VERSION 5.8 ;
BUSBITCHARS "[]" ;
DIVIDERCHAR "/" ;
UNITS
  DATABASE MICRONS 1000 ;
END UNITS
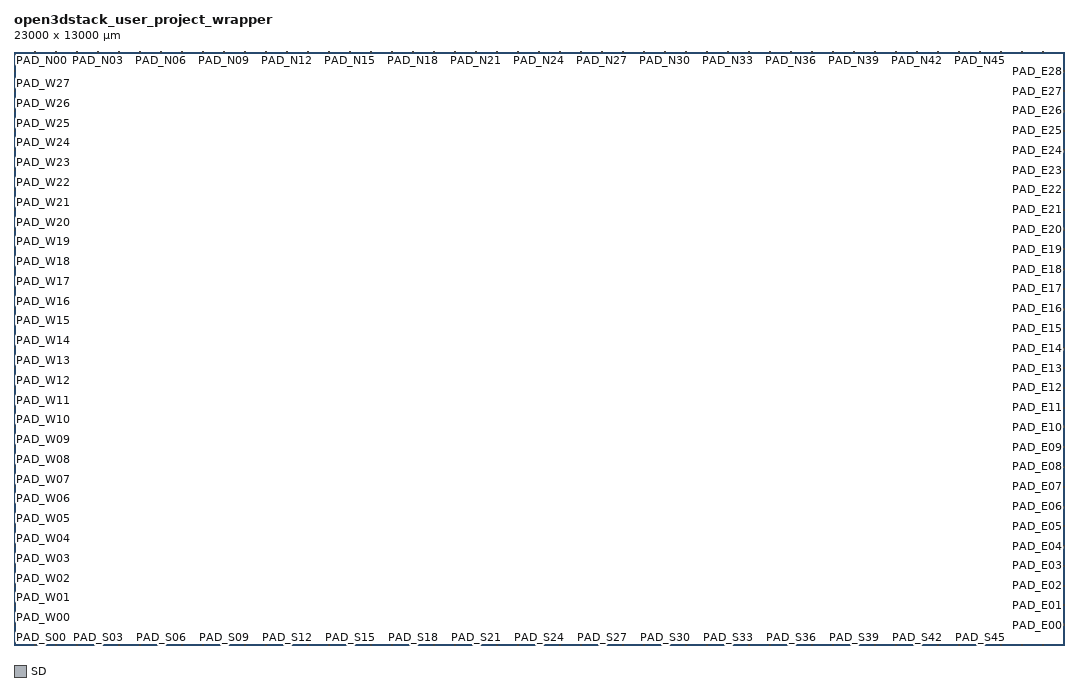
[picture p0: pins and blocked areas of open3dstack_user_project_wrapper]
MACRO open3dstack_user_project_wrapper
  CLASS BLOCK ;
  ORIGIN 0 0 ;
  FOREIGN open3dstack_user_project_wrapper 0 0 ;
  SIZE 23000 BY 13000 ;
  SYMMETRY X Y ;
  PIN PAD_S00
    DIRECTION INOUT ;
    USE SIGNAL ;
    PORT
      LAYER SD ;
        RECT 450 0 470 20 ;
    END
  END PAD_S00
  PIN PAD_S01
    DIRECTION INOUT ;
    USE SIGNAL ;
    PORT
      LAYER SD ;
        RECT 910 0 930 20 ;
    END
  END PAD_S01
  PIN PAD_S02
    DIRECTION INOUT ;
    USE SIGNAL ;
    PORT
      LAYER SD ;
        RECT 1370 0 1390 20 ;
    END
  END PAD_S02
  PIN PAD_S03
    DIRECTION INOUT ;
    USE SIGNAL ;
    PORT
      LAYER SD ;
        RECT 1830 0 1850 20 ;
    END
  END PAD_S03
  PIN PAD_S04
    DIRECTION INOUT ;
    USE SIGNAL ;
    PORT
      LAYER SD ;
        RECT 2290 0 2310 20 ;
    END
  END PAD_S04
  PIN PAD_S05
    DIRECTION INOUT ;
    USE SIGNAL ;
    PORT
      LAYER SD ;
        RECT 2750 0 2770 20 ;
    END
  END PAD_S05
  PIN PAD_S06
    DIRECTION INOUT ;
    USE SIGNAL ;
    PORT
      LAYER SD ;
        RECT 3210 0 3230 20 ;
    END
  END PAD_S06
  PIN PAD_S07
    DIRECTION INOUT ;
    USE SIGNAL ;
    PORT
      LAYER SD ;
        RECT 3670 0 3690 20 ;
    END
  END PAD_S07
  PIN PAD_S08
    DIRECTION INOUT ;
    USE SIGNAL ;
    PORT
      LAYER SD ;
        RECT 4130 0 4150 20 ;
    END
  END PAD_S08
  PIN PAD_S09
    DIRECTION INOUT ;
    USE SIGNAL ;
    PORT
      LAYER SD ;
        RECT 4590 0 4610 20 ;
    END
  END PAD_S09
  PIN PAD_S10
    DIRECTION INOUT ;
    USE SIGNAL ;
    PORT
      LAYER SD ;
        RECT 5050 0 5070 20 ;
    END
  END PAD_S10
  PIN PAD_S11
    DIRECTION INOUT ;
    USE SIGNAL ;
    PORT
      LAYER SD ;
        RECT 5510 0 5530 20 ;
    END
  END PAD_S11
  PIN PAD_S12
    DIRECTION INOUT ;
    USE SIGNAL ;
    PORT
      LAYER SD ;
        RECT 5970 0 5990 20 ;
    END
  END PAD_S12
  PIN PAD_S13
    DIRECTION INOUT ;
    USE SIGNAL ;
    PORT
      LAYER SD ;
        RECT 6430 0 6450 20 ;
    END
  END PAD_S13
  PIN PAD_S14
    DIRECTION INOUT ;
    USE SIGNAL ;
    PORT
      LAYER SD ;
        RECT 6890 0 6910 20 ;
    END
  END PAD_S14
  PIN PAD_S15
    DIRECTION INOUT ;
    USE SIGNAL ;
    PORT
      LAYER SD ;
        RECT 7350 0 7370 20 ;
    END
  END PAD_S15
  PIN PAD_S16
    DIRECTION INOUT ;
    USE SIGNAL ;
    PORT
      LAYER SD ;
        RECT 7810 0 7830 20 ;
    END
  END PAD_S16
  PIN PAD_S17
    DIRECTION INOUT ;
    USE SIGNAL ;
    PORT
      LAYER SD ;
        RECT 8270 0 8290 20 ;
    END
  END PAD_S17
  PIN PAD_S18
    DIRECTION INOUT ;
    USE SIGNAL ;
    PORT
      LAYER SD ;
        RECT 8730 0 8750 20 ;
    END
  END PAD_S18
  PIN PAD_S19
    DIRECTION INOUT ;
    USE SIGNAL ;
    PORT
      LAYER SD ;
        RECT 9190 0 9210 20 ;
    END
  END PAD_S19
  PIN PAD_S20
    DIRECTION INOUT ;
    USE SIGNAL ;
    PORT
      LAYER SD ;
        RECT 9650 0 9670 20 ;
    END
  END PAD_S20
  PIN PAD_S21
    DIRECTION INOUT ;
    USE SIGNAL ;
    PORT
      LAYER SD ;
        RECT 10110 0 10130 20 ;
    END
  END PAD_S21
  PIN PAD_S22
    DIRECTION INOUT ;
    USE SIGNAL ;
    PORT
      LAYER SD ;
        RECT 10570 0 10590 20 ;
    END
  END PAD_S22
  PIN PAD_S23
    DIRECTION INOUT ;
    USE SIGNAL ;
    PORT
      LAYER SD ;
        RECT 11030 0 11050 20 ;
    END
  END PAD_S23
  PIN PAD_S24
    DIRECTION INOUT ;
    USE SIGNAL ;
    PORT
      LAYER SD ;
        RECT 11490 0 11510 20 ;
    END
  END PAD_S24
  PIN PAD_S25
    DIRECTION INOUT ;
    USE SIGNAL ;
    PORT
      LAYER SD ;
        RECT 11950 0 11970 20 ;
    END
  END PAD_S25
  PIN PAD_S26
    DIRECTION INOUT ;
    USE SIGNAL ;
    PORT
      LAYER SD ;
        RECT 12410 0 12430 20 ;
    END
  END PAD_S26
  PIN PAD_S27
    DIRECTION INOUT ;
    USE SIGNAL ;
    PORT
      LAYER SD ;
        RECT 12870 0 12890 20 ;
    END
  END PAD_S27
  PIN PAD_S28
    DIRECTION INOUT ;
    USE SIGNAL ;
    PORT
      LAYER SD ;
        RECT 13330 0 13350 20 ;
    END
  END PAD_S28
  PIN PAD_S29
    DIRECTION INOUT ;
    USE SIGNAL ;
    PORT
      LAYER SD ;
        RECT 13790 0 13810 20 ;
    END
  END PAD_S29
  PIN PAD_S30
    DIRECTION INOUT ;
    USE SIGNAL ;
    PORT
      LAYER SD ;
        RECT 14250 0 14270 20 ;
    END
  END PAD_S30
  PIN PAD_S31
    DIRECTION INOUT ;
    USE SIGNAL ;
    PORT
      LAYER SD ;
        RECT 14710 0 14730 20 ;
    END
  END PAD_S31
  PIN PAD_S32
    DIRECTION INOUT ;
    USE SIGNAL ;
    PORT
      LAYER SD ;
        RECT 15170 0 15190 20 ;
    END
  END PAD_S32
  PIN PAD_S33
    DIRECTION INOUT ;
    USE SIGNAL ;
    PORT
      LAYER SD ;
        RECT 15630 0 15650 20 ;
    END
  END PAD_S33
  PIN PAD_S34
    DIRECTION INOUT ;
    USE SIGNAL ;
    PORT
      LAYER SD ;
        RECT 16090 0 16110 20 ;
    END
  END PAD_S34
  PIN PAD_S35
    DIRECTION INOUT ;
    USE SIGNAL ;
    PORT
      LAYER SD ;
        RECT 16550 0 16570 20 ;
    END
  END PAD_S35
  PIN PAD_S36
    DIRECTION INOUT ;
    USE SIGNAL ;
    PORT
      LAYER SD ;
        RECT 17010 0 17030 20 ;
    END
  END PAD_S36
  PIN PAD_S37
    DIRECTION INOUT ;
    USE SIGNAL ;
    PORT
      LAYER SD ;
        RECT 17470 0 17490 20 ;
    END
  END PAD_S37
  PIN PAD_S38
    DIRECTION INOUT ;
    USE SIGNAL ;
    PORT
      LAYER SD ;
        RECT 17930 0 17950 20 ;
    END
  END PAD_S38
  PIN PAD_S39
    DIRECTION INOUT ;
    USE SIGNAL ;
    PORT
      LAYER SD ;
        RECT 18390 0 18410 20 ;
    END
  END PAD_S39
  PIN PAD_S40
    DIRECTION INOUT ;
    USE SIGNAL ;
    PORT
      LAYER SD ;
        RECT 18850 0 18870 20 ;
    END
  END PAD_S40
  PIN PAD_S41
    DIRECTION INOUT ;
    USE SIGNAL ;
    PORT
      LAYER SD ;
        RECT 19310 0 19330 20 ;
    END
  END PAD_S41
  PIN PAD_S42
    DIRECTION INOUT ;
    USE SIGNAL ;
    PORT
      LAYER SD ;
        RECT 19770 0 19790 20 ;
    END
  END PAD_S42
  PIN PAD_S43
    DIRECTION INOUT ;
    USE SIGNAL ;
    PORT
      LAYER SD ;
        RECT 20230 0 20250 20 ;
    END
  END PAD_S43
  PIN PAD_S44
    DIRECTION INOUT ;
    USE SIGNAL ;
    PORT
      LAYER SD ;
        RECT 20690 0 20710 20 ;
    END
  END PAD_S44
  PIN PAD_S45
    DIRECTION INOUT ;
    USE SIGNAL ;
    PORT
      LAYER SD ;
        RECT 21150 0 21170 20 ;
    END
  END PAD_S45
  PIN PAD_S46
    DIRECTION INOUT ;
    USE SIGNAL ;
    PORT
      LAYER SD ;
        RECT 21610 0 21630 20 ;
    END
  END PAD_S46
  PIN PAD_S47
    DIRECTION INOUT ;
    USE SIGNAL ;
    PORT
      LAYER SD ;
        RECT 22070 0 22090 20 ;
    END
  END PAD_S47
  PIN PAD_S48
    DIRECTION INOUT ;
    USE SIGNAL ;
    PORT
      LAYER SD ;
        RECT 22530 0 22550 20 ;
    END
  END PAD_S48
  PIN PAD_E00
    DIRECTION INOUT ;
    USE SIGNAL ;
    PORT
      LAYER SD ;
        RECT 22980 423.333 23000 443.333 ;
    END
  END PAD_E00
  PIN PAD_E01
    DIRECTION INOUT ;
    USE SIGNAL ;
    PORT
      LAYER SD ;
        RECT 22980 856.667 23000 876.667 ;
    END
  END PAD_E01
  PIN PAD_E02
    DIRECTION INOUT ;
    USE SIGNAL ;
    PORT
      LAYER SD ;
        RECT 22980 1290 23000 1310 ;
    END
  END PAD_E02
  PIN PAD_E03
    DIRECTION INOUT ;
    USE SIGNAL ;
    PORT
      LAYER SD ;
        RECT 22980 1723.333 23000 1743.333 ;
    END
  END PAD_E03
  PIN PAD_E04
    DIRECTION INOUT ;
    USE SIGNAL ;
    PORT
      LAYER SD ;
        RECT 22980 2156.667 23000 2176.667 ;
    END
  END PAD_E04
  PIN PAD_E05
    DIRECTION INOUT ;
    USE SIGNAL ;
    PORT
      LAYER SD ;
        RECT 22980 2590 23000 2610 ;
    END
  END PAD_E05
  PIN PAD_E06
    DIRECTION INOUT ;
    USE SIGNAL ;
    PORT
      LAYER SD ;
        RECT 22980 3023.333 23000 3043.333 ;
    END
  END PAD_E06
  PIN PAD_E07
    DIRECTION INOUT ;
    USE SIGNAL ;
    PORT
      LAYER SD ;
        RECT 22980 3456.667 23000 3476.667 ;
    END
  END PAD_E07
  PIN PAD_E08
    DIRECTION INOUT ;
    USE SIGNAL ;
    PORT
      LAYER SD ;
        RECT 22980 3890 23000 3910 ;
    END
  END PAD_E08
  PIN PAD_E09
    DIRECTION INOUT ;
    USE SIGNAL ;
    PORT
      LAYER SD ;
        RECT 22980 4323.333 23000 4343.333 ;
    END
  END PAD_E09
  PIN PAD_E10
    DIRECTION INOUT ;
    USE SIGNAL ;
    PORT
      LAYER SD ;
        RECT 22980 4756.667 23000 4776.667 ;
    END
  END PAD_E10
  PIN PAD_E11
    DIRECTION INOUT ;
    USE SIGNAL ;
    PORT
      LAYER SD ;
        RECT 22980 5190 23000 5210 ;
    END
  END PAD_E11
  PIN PAD_E12
    DIRECTION INOUT ;
    USE SIGNAL ;
    PORT
      LAYER SD ;
        RECT 22980 5623.333 23000 5643.333 ;
    END
  END PAD_E12
  PIN PAD_E13
    DIRECTION INOUT ;
    USE SIGNAL ;
    PORT
      LAYER SD ;
        RECT 22980 6056.667 23000 6076.667 ;
    END
  END PAD_E13
  PIN PAD_E14
    DIRECTION INOUT ;
    USE SIGNAL ;
    PORT
      LAYER SD ;
        RECT 22980 6490 23000 6510 ;
    END
  END PAD_E14
  PIN PAD_E15
    DIRECTION INOUT ;
    USE SIGNAL ;
    PORT
      LAYER SD ;
        RECT 22980 6923.333 23000 6943.333 ;
    END
  END PAD_E15
  PIN PAD_E16
    DIRECTION INOUT ;
    USE SIGNAL ;
    PORT
      LAYER SD ;
        RECT 22980 7356.667 23000 7376.667 ;
    END
  END PAD_E16
  PIN PAD_E17
    DIRECTION INOUT ;
    USE SIGNAL ;
    PORT
      LAYER SD ;
        RECT 22980 7790 23000 7810 ;
    END
  END PAD_E17
  PIN PAD_E18
    DIRECTION INOUT ;
    USE SIGNAL ;
    PORT
      LAYER SD ;
        RECT 22980 8223.333 23000 8243.333 ;
    END
  END PAD_E18
  PIN PAD_E19
    DIRECTION INOUT ;
    USE SIGNAL ;
    PORT
      LAYER SD ;
        RECT 22980 8656.667 23000 8676.667 ;
    END
  END PAD_E19
  PIN PAD_E20
    DIRECTION INOUT ;
    USE SIGNAL ;
    PORT
      LAYER SD ;
        RECT 22980 9090 23000 9110 ;
    END
  END PAD_E20
  PIN PAD_E21
    DIRECTION INOUT ;
    USE SIGNAL ;
    PORT
      LAYER SD ;
        RECT 22980 9523.333 23000 9543.333 ;
    END
  END PAD_E21
  PIN PAD_E22
    DIRECTION INOUT ;
    USE SIGNAL ;
    PORT
      LAYER SD ;
        RECT 22980 9956.667 23000 9976.667 ;
    END
  END PAD_E22
  PIN PAD_E23
    DIRECTION INOUT ;
    USE SIGNAL ;
    PORT
      LAYER SD ;
        RECT 22980 10390 23000 10410 ;
    END
  END PAD_E23
  PIN PAD_E24
    DIRECTION INOUT ;
    USE SIGNAL ;
    PORT
      LAYER SD ;
        RECT 22980 10823.333 23000 10843.333 ;
    END
  END PAD_E24
  PIN PAD_E25
    DIRECTION INOUT ;
    USE SIGNAL ;
    PORT
      LAYER SD ;
        RECT 22980 11256.667 23000 11276.667 ;
    END
  END PAD_E25
  PIN PAD_E26
    DIRECTION INOUT ;
    USE SIGNAL ;
    PORT
      LAYER SD ;
        RECT 22980 11690 23000 11710 ;
    END
  END PAD_E26
  PIN PAD_E27
    DIRECTION INOUT ;
    USE SIGNAL ;
    PORT
      LAYER SD ;
        RECT 22980 12123.333 23000 12143.333 ;
    END
  END PAD_E27
  PIN PAD_E28
    DIRECTION INOUT ;
    USE SIGNAL ;
    PORT
      LAYER SD ;
        RECT 22980 12556.667 23000 12576.667 ;
    END
  END PAD_E28
  PIN PAD_N00
    DIRECTION INOUT ;
    USE SIGNAL ;
    PORT
      LAYER SD ;
        RECT 450 12980 470 13000 ;
    END
  END PAD_N00
  PIN PAD_N01
    DIRECTION INOUT ;
    USE SIGNAL ;
    PORT
      LAYER SD ;
        RECT 910 12980 930 13000 ;
    END
  END PAD_N01
  PIN PAD_N02
    DIRECTION INOUT ;
    USE SIGNAL ;
    PORT
      LAYER SD ;
        RECT 1370 12980 1390 13000 ;
    END
  END PAD_N02
  PIN PAD_N03
    DIRECTION INOUT ;
    USE SIGNAL ;
    PORT
      LAYER SD ;
        RECT 1830 12980 1850 13000 ;
    END
  END PAD_N03
  PIN PAD_N04
    DIRECTION INOUT ;
    USE SIGNAL ;
    PORT
      LAYER SD ;
        RECT 2290 12980 2310 13000 ;
    END
  END PAD_N04
  PIN PAD_N05
    DIRECTION INOUT ;
    USE SIGNAL ;
    PORT
      LAYER SD ;
        RECT 2750 12980 2770 13000 ;
    END
  END PAD_N05
  PIN PAD_N06
    DIRECTION INOUT ;
    USE SIGNAL ;
    PORT
      LAYER SD ;
        RECT 3210 12980 3230 13000 ;
    END
  END PAD_N06
  PIN PAD_N07
    DIRECTION INOUT ;
    USE SIGNAL ;
    PORT
      LAYER SD ;
        RECT 3670 12980 3690 13000 ;
    END
  END PAD_N07
  PIN PAD_N08
    DIRECTION INOUT ;
    USE SIGNAL ;
    PORT
      LAYER SD ;
        RECT 4130 12980 4150 13000 ;
    END
  END PAD_N08
  PIN PAD_N09
    DIRECTION INOUT ;
    USE SIGNAL ;
    PORT
      LAYER SD ;
        RECT 4590 12980 4610 13000 ;
    END
  END PAD_N09
  PIN PAD_N10
    DIRECTION INOUT ;
    USE SIGNAL ;
    PORT
      LAYER SD ;
        RECT 5050 12980 5070 13000 ;
    END
  END PAD_N10
  PIN PAD_N11
    DIRECTION INOUT ;
    USE SIGNAL ;
    PORT
      LAYER SD ;
        RECT 5510 12980 5530 13000 ;
    END
  END PAD_N11
  PIN PAD_N12
    DIRECTION INOUT ;
    USE SIGNAL ;
    PORT
      LAYER SD ;
        RECT 5970 12980 5990 13000 ;
    END
  END PAD_N12
  PIN PAD_N13
    DIRECTION INOUT ;
    USE SIGNAL ;
    PORT
      LAYER SD ;
        RECT 6430 12980 6450 13000 ;
    END
  END PAD_N13
  PIN PAD_N14
    DIRECTION INOUT ;
    USE SIGNAL ;
    PORT
      LAYER SD ;
        RECT 6890 12980 6910 13000 ;
    END
  END PAD_N14
  PIN PAD_N15
    DIRECTION INOUT ;
    USE SIGNAL ;
    PORT
      LAYER SD ;
        RECT 7350 12980 7370 13000 ;
    END
  END PAD_N15
  PIN PAD_N16
    DIRECTION INOUT ;
    USE SIGNAL ;
    PORT
      LAYER SD ;
        RECT 7810 12980 7830 13000 ;
    END
  END PAD_N16
  PIN PAD_N17
    DIRECTION INOUT ;
    USE SIGNAL ;
    PORT
      LAYER SD ;
        RECT 8270 12980 8290 13000 ;
    END
  END PAD_N17
  PIN PAD_N18
    DIRECTION INOUT ;
    USE SIGNAL ;
    PORT
      LAYER SD ;
        RECT 8730 12980 8750 13000 ;
    END
  END PAD_N18
  PIN PAD_N19
    DIRECTION INOUT ;
    USE SIGNAL ;
    PORT
      LAYER SD ;
        RECT 9190 12980 9210 13000 ;
    END
  END PAD_N19
  PIN PAD_N20
    DIRECTION INOUT ;
    USE SIGNAL ;
    PORT
      LAYER SD ;
        RECT 9650 12980 9670 13000 ;
    END
  END PAD_N20
  PIN PAD_N21
    DIRECTION INOUT ;
    USE SIGNAL ;
    PORT
      LAYER SD ;
        RECT 10110 12980 10130 13000 ;
    END
  END PAD_N21
  PIN PAD_N22
    DIRECTION INOUT ;
    USE SIGNAL ;
    PORT
      LAYER SD ;
        RECT 10570 12980 10590 13000 ;
    END
  END PAD_N22
  PIN PAD_N23
    DIRECTION INOUT ;
    USE SIGNAL ;
    PORT
      LAYER SD ;
        RECT 11030 12980 11050 13000 ;
    END
  END PAD_N23
  PIN PAD_N24
    DIRECTION INOUT ;
    USE SIGNAL ;
    PORT
      LAYER SD ;
        RECT 11490 12980 11510 13000 ;
    END
  END PAD_N24
  PIN PAD_N25
    DIRECTION INOUT ;
    USE SIGNAL ;
    PORT
      LAYER SD ;
        RECT 11950 12980 11970 13000 ;
    END
  END PAD_N25
  PIN PAD_N26
    DIRECTION INOUT ;
    USE SIGNAL ;
    PORT
      LAYER SD ;
        RECT 12410 12980 12430 13000 ;
    END
  END PAD_N26
  PIN PAD_N27
    DIRECTION INOUT ;
    USE SIGNAL ;
    PORT
      LAYER SD ;
        RECT 12870 12980 12890 13000 ;
    END
  END PAD_N27
  PIN PAD_N28
    DIRECTION INOUT ;
    USE SIGNAL ;
    PORT
      LAYER SD ;
        RECT 13330 12980 13350 13000 ;
    END
  END PAD_N28
  PIN PAD_N29
    DIRECTION INOUT ;
    USE SIGNAL ;
    PORT
      LAYER SD ;
        RECT 13790 12980 13810 13000 ;
    END
  END PAD_N29
  PIN PAD_N30
    DIRECTION INOUT ;
    USE SIGNAL ;
    PORT
      LAYER SD ;
        RECT 14250 12980 14270 13000 ;
    END
  END PAD_N30
  PIN PAD_N31
    DIRECTION INOUT ;
    USE SIGNAL ;
    PORT
      LAYER SD ;
        RECT 14710 12980 14730 13000 ;
    END
  END PAD_N31
  PIN PAD_N32
    DIRECTION INOUT ;
    USE SIGNAL ;
    PORT
      LAYER SD ;
        RECT 15170 12980 15190 13000 ;
    END
  END PAD_N32
  PIN PAD_N33
    DIRECTION INOUT ;
    USE SIGNAL ;
    PORT
      LAYER SD ;
        RECT 15630 12980 15650 13000 ;
    END
  END PAD_N33
  PIN PAD_N34
    DIRECTION INOUT ;
    USE SIGNAL ;
    PORT
      LAYER SD ;
        RECT 16090 12980 16110 13000 ;
    END
  END PAD_N34
  PIN PAD_N35
    DIRECTION INOUT ;
    USE SIGNAL ;
    PORT
      LAYER SD ;
        RECT 16550 12980 16570 13000 ;
    END
  END PAD_N35
  PIN PAD_N36
    DIRECTION INOUT ;
    USE SIGNAL ;
    PORT
      LAYER SD ;
        RECT 17010 12980 17030 13000 ;
    END
  END PAD_N36
  PIN PAD_N37
    DIRECTION INOUT ;
    USE SIGNAL ;
    PORT
      LAYER SD ;
        RECT 17470 12980 17490 13000 ;
    END
  END PAD_N37
  PIN PAD_N38
    DIRECTION INOUT ;
    USE SIGNAL ;
    PORT
      LAYER SD ;
        RECT 17930 12980 17950 13000 ;
    END
  END PAD_N38
  PIN PAD_N39
    DIRECTION INOUT ;
    USE SIGNAL ;
    PORT
      LAYER SD ;
        RECT 18390 12980 18410 13000 ;
    END
  END PAD_N39
  PIN PAD_N40
    DIRECTION INOUT ;
    USE SIGNAL ;
    PORT
      LAYER SD ;
        RECT 18850 12980 18870 13000 ;
    END
  END PAD_N40
  PIN PAD_N41
    DIRECTION INOUT ;
    USE SIGNAL ;
    PORT
      LAYER SD ;
        RECT 19310 12980 19330 13000 ;
    END
  END PAD_N41
  PIN PAD_N42
    DIRECTION INOUT ;
    USE SIGNAL ;
    PORT
      LAYER SD ;
        RECT 19770 12980 19790 13000 ;
    END
  END PAD_N42
  PIN PAD_N43
    DIRECTION INOUT ;
    USE SIGNAL ;
    PORT
      LAYER SD ;
        RECT 20230 12980 20250 13000 ;
    END
  END PAD_N43
  PIN PAD_N44
    DIRECTION INOUT ;
    USE SIGNAL ;
    PORT
      LAYER SD ;
        RECT 20690 12980 20710 13000 ;
    END
  END PAD_N44
  PIN PAD_N45
    DIRECTION INOUT ;
    USE SIGNAL ;
    PORT
      LAYER SD ;
        RECT 21150 12980 21170 13000 ;
    END
  END PAD_N45
  PIN PAD_N46
    DIRECTION INOUT ;
    USE SIGNAL ;
    PORT
      LAYER SD ;
        RECT 21610 12980 21630 13000 ;
    END
  END PAD_N46
  PIN PAD_N47
    DIRECTION INOUT ;
    USE SIGNAL ;
    PORT
      LAYER SD ;
        RECT 22070 12980 22090 13000 ;
    END
  END PAD_N47
  PIN PAD_N48
    DIRECTION INOUT ;
    USE SIGNAL ;
    PORT
      LAYER SD ;
        RECT 22530 12980 22550 13000 ;
    END
  END PAD_N48
  PIN PAD_W00
    DIRECTION INOUT ;
    USE SIGNAL ;
    PORT
      LAYER SD ;
        RECT 0 423.333 20 443.333 ;
    END
  END PAD_W00
  PIN PAD_W01
    DIRECTION INOUT ;
    USE SIGNAL ;
    PORT
      LAYER SD ;
        RECT 0 856.667 20 876.667 ;
    END
  END PAD_W01
  PIN PAD_W02
    DIRECTION INOUT ;
    USE SIGNAL ;
    PORT
      LAYER SD ;
        RECT 0 1290 20 1310 ;
    END
  END PAD_W02
  PIN PAD_W03
    DIRECTION INOUT ;
    USE SIGNAL ;
    PORT
      LAYER SD ;
        RECT 0 1723.333 20 1743.333 ;
    END
  END PAD_W03
  PIN PAD_W04
    DIRECTION INOUT ;
    USE SIGNAL ;
    PORT
      LAYER SD ;
        RECT 0 2156.667 20 2176.667 ;
    END
  END PAD_W04
  PIN PAD_W05
    DIRECTION INOUT ;
    USE SIGNAL ;
    PORT
      LAYER SD ;
        RECT 0 2590 20 2610 ;
    END
  END PAD_W05
  PIN PAD_W06
    DIRECTION INOUT ;
    USE SIGNAL ;
    PORT
      LAYER SD ;
        RECT 0 3023.333 20 3043.333 ;
    END
  END PAD_W06
  PIN PAD_W07
    DIRECTION INOUT ;
    USE SIGNAL ;
    PORT
      LAYER SD ;
        RECT 0 3456.667 20 3476.667 ;
    END
  END PAD_W07
  PIN PAD_W08
    DIRECTION INOUT ;
    USE SIGNAL ;
    PORT
      LAYER SD ;
        RECT 0 3890 20 3910 ;
    END
  END PAD_W08
  PIN PAD_W09
    DIRECTION INOUT ;
    USE SIGNAL ;
    PORT
      LAYER SD ;
        RECT 0 4323.333 20 4343.333 ;
    END
  END PAD_W09
  PIN PAD_W10
    DIRECTION INOUT ;
    USE SIGNAL ;
    PORT
      LAYER SD ;
        RECT 0 4756.667 20 4776.667 ;
    END
  END PAD_W10
  PIN PAD_W11
    DIRECTION INOUT ;
    USE SIGNAL ;
    PORT
      LAYER SD ;
        RECT 0 5190 20 5210 ;
    END
  END PAD_W11
  PIN PAD_W12
    DIRECTION INOUT ;
    USE SIGNAL ;
    PORT
      LAYER SD ;
        RECT 0 5623.333 20 5643.333 ;
    END
  END PAD_W12
  PIN PAD_W13
    DIRECTION INOUT ;
    USE SIGNAL ;
    PORT
      LAYER SD ;
        RECT 0 6056.667 20 6076.667 ;
    END
  END PAD_W13
  PIN PAD_W14
    DIRECTION INOUT ;
    USE SIGNAL ;
    PORT
      LAYER SD ;
        RECT 0 6490 20 6510 ;
    END
  END PAD_W14
  PIN PAD_W15
    DIRECTION INOUT ;
    USE SIGNAL ;
    PORT
      LAYER SD ;
        RECT 0 6923.333 20 6943.333 ;
    END
  END PAD_W15
  PIN PAD_W16
    DIRECTION INOUT ;
    USE SIGNAL ;
    PORT
      LAYER SD ;
        RECT 0 7356.667 20 7376.667 ;
    END
  END PAD_W16
  PIN PAD_W17
    DIRECTION INOUT ;
    USE SIGNAL ;
    PORT
      LAYER SD ;
        RECT 0 7790 20 7810 ;
    END
  END PAD_W17
  PIN PAD_W18
    DIRECTION INOUT ;
    USE SIGNAL ;
    PORT
      LAYER SD ;
        RECT 0 8223.333 20 8243.333 ;
    END
  END PAD_W18
  PIN PAD_W19
    DIRECTION INOUT ;
    USE SIGNAL ;
    PORT
      LAYER SD ;
        RECT 0 8656.667 20 8676.667 ;
    END
  END PAD_W19
  PIN PAD_W20
    DIRECTION INOUT ;
    USE SIGNAL ;
    PORT
      LAYER SD ;
        RECT 0 9090 20 9110 ;
    END
  END PAD_W20
  PIN PAD_W21
    DIRECTION INOUT ;
    USE SIGNAL ;
    PORT
      LAYER SD ;
        RECT 0 9523.333 20 9543.333 ;
    END
  END PAD_W21
  PIN PAD_W22
    DIRECTION INOUT ;
    USE SIGNAL ;
    PORT
      LAYER SD ;
        RECT 0 9956.667 20 9976.667 ;
    END
  END PAD_W22
  PIN PAD_W23
    DIRECTION INOUT ;
    USE SIGNAL ;
    PORT
      LAYER SD ;
        RECT 0 10390 20 10410 ;
    END
  END PAD_W23
  PIN PAD_W24
    DIRECTION INOUT ;
    USE SIGNAL ;
    PORT
      LAYER SD ;
        RECT 0 10823.333 20 10843.333 ;
    END
  END PAD_W24
  PIN PAD_W25
    DIRECTION INOUT ;
    USE SIGNAL ;
    PORT
      LAYER SD ;
        RECT 0 11256.667 20 11276.667 ;
    END
  END PAD_W25
  PIN PAD_W26
    DIRECTION INOUT ;
    USE SIGNAL ;
    PORT
      LAYER SD ;
        RECT 0 11690 20 11710 ;
    END
  END PAD_W26
  PIN PAD_W27
    DIRECTION INOUT ;
    USE SIGNAL ;
    PORT
      LAYER SD ;
        RECT 0 12123.333 20 12143.333 ;
    END
  END PAD_W27
  PIN PAD_W28
    DIRECTION INOUT ;
    USE SIGNAL ;
    PORT
      LAYER SD ;
        RECT 0 12556.667 20 12576.667 ;
    END
  END PAD_W28
END open3dstack_user_project_wrapper
END LIBRARY
